VERSION 5.4 ;
NAMESCASESENSITIVE ON ;
BUSBITCHARS "[]" ;
DIVIDERCHAR "/" ;
UNITS
  DATABASE MICRONS 2000 ;
END UNITS
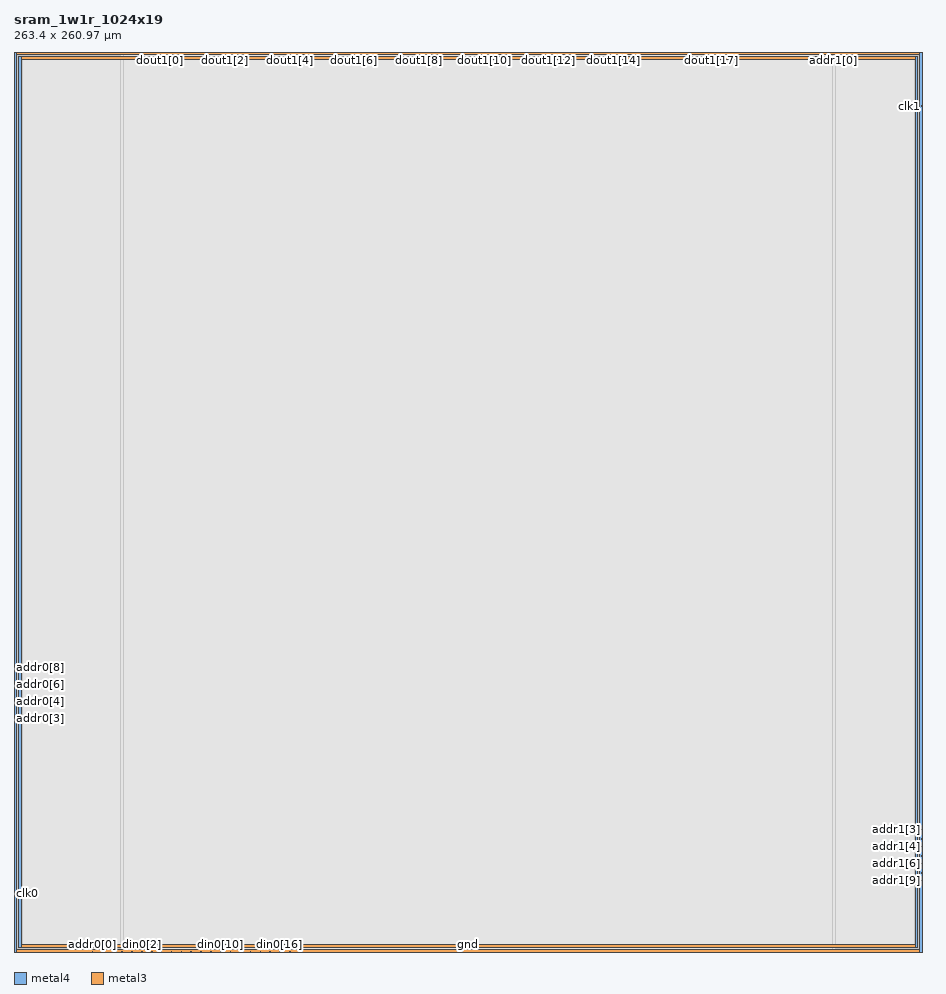
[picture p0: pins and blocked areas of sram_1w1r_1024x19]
MACRO sram_1w1r_1024x19
   CLASS BLOCK ;
   SIZE 263.4 BY 260.97 ;
   SYMMETRY X Y R90 ;
   PIN din0[0]
      DIRECTION INPUT ;
      PORT
         LAYER metal4 ;
         RECT  31.3 0.0 31.44 0.14 ;
      END
   END din0[0]
   PIN din0[1]
      DIRECTION INPUT ;
      PORT
         LAYER metal4 ;
         RECT  34.16 0.0 34.3 0.14 ;
      END
   END din0[1]
   PIN din0[2]
      DIRECTION INPUT ;
      PORT
         LAYER metal4 ;
         RECT  37.02 0.0 37.16 0.14 ;
      END
   END din0[2]
   PIN din0[3]
      DIRECTION INPUT ;
      PORT
         LAYER metal4 ;
         RECT  39.88 0.0 40.02 0.14 ;
      END
   END din0[3]
   PIN din0[4]
      DIRECTION INPUT ;
      PORT
         LAYER metal4 ;
         RECT  42.74 0.0 42.88 0.14 ;
      END
   END din0[4]
   PIN din0[5]
      DIRECTION INPUT ;
      PORT
         LAYER metal4 ;
         RECT  45.6 0.0 45.74 0.14 ;
      END
   END din0[5]
   PIN din0[6]
      DIRECTION INPUT ;
      PORT
         LAYER metal4 ;
         RECT  48.46 0.0 48.6 0.14 ;
      END
   END din0[6]
   PIN din0[7]
      DIRECTION INPUT ;
      PORT
         LAYER metal4 ;
         RECT  51.32 0.0 51.46 0.14 ;
      END
   END din0[7]
   PIN din0[8]
      DIRECTION INPUT ;
      PORT
         LAYER metal4 ;
         RECT  54.18 0.0 54.32 0.14 ;
      END
   END din0[8]
   PIN din0[9]
      DIRECTION INPUT ;
      PORT
         LAYER metal4 ;
         RECT  57.04 0.0 57.18 0.14 ;
      END
   END din0[9]
   PIN din0[10]
      DIRECTION INPUT ;
      PORT
         LAYER metal4 ;
         RECT  59.9 0.0 60.04 0.14 ;
      END
   END din0[10]
   PIN din0[11]
      DIRECTION INPUT ;
      PORT
         LAYER metal4 ;
         RECT  62.76 0.0 62.9 0.14 ;
      END
   END din0[11]
   PIN din0[12]
      DIRECTION INPUT ;
      PORT
         LAYER metal4 ;
         RECT  65.62 0.0 65.76 0.14 ;
      END
   END din0[12]
   PIN din0[13]
      DIRECTION INPUT ;
      PORT
         LAYER metal4 ;
         RECT  68.48 0.0 68.62 0.14 ;
      END
   END din0[13]
   PIN din0[14]
      DIRECTION INPUT ;
      PORT
         LAYER metal4 ;
         RECT  71.34 0.0 71.48 0.14 ;
      END
   END din0[14]
   PIN din0[15]
      DIRECTION INPUT ;
      PORT
         LAYER metal4 ;
         RECT  74.2 0.0 74.34 0.14 ;
      END
   END din0[15]
   PIN din0[16]
      DIRECTION INPUT ;
      PORT
         LAYER metal4 ;
         RECT  77.06 0.0 77.2 0.14 ;
      END
   END din0[16]
   PIN din0[17]
      DIRECTION INPUT ;
      PORT
         LAYER metal4 ;
         RECT  79.92 0.0 80.06 0.14 ;
      END
   END din0[17]
   PIN din0[18]
      DIRECTION INPUT ;
      PORT
         LAYER metal4 ;
         RECT  82.78 0.0 82.92 0.14 ;
      END
   END din0[18]
   PIN addr0[0]
      DIRECTION INPUT ;
      PORT
         LAYER metal4 ;
         RECT  22.72 0.0 22.86 0.14 ;
      END
   END addr0[0]
   PIN addr0[1]
      DIRECTION INPUT ;
      PORT
         LAYER metal4 ;
         RECT  25.58 0.0 25.72 0.14 ;
      END
   END addr0[1]
   PIN addr0[2]
      DIRECTION INPUT ;
      PORT
         LAYER metal4 ;
         RECT  28.44 0.0 28.58 0.14 ;
      END
   END addr0[2]
   PIN addr0[3]
      DIRECTION INPUT ;
      PORT
         LAYER metal3 ;
         RECT  0.0 67.6 0.14 67.74 ;
      END
   END addr0[3]
   PIN addr0[4]
      DIRECTION INPUT ;
      PORT
         LAYER metal3 ;
         RECT  0.0 70.33 0.14 70.47 ;
      END
   END addr0[4]
   PIN addr0[5]
      DIRECTION INPUT ;
      PORT
         LAYER metal3 ;
         RECT  0.0 72.54 0.14 72.68 ;
      END
   END addr0[5]
   PIN addr0[6]
      DIRECTION INPUT ;
      PORT
         LAYER metal3 ;
         RECT  0.0 75.27 0.14 75.41 ;
      END
   END addr0[6]
   PIN addr0[7]
      DIRECTION INPUT ;
      PORT
         LAYER metal3 ;
         RECT  0.0 77.48 0.14 77.62 ;
      END
   END addr0[7]
   PIN addr0[8]
      DIRECTION INPUT ;
      PORT
         LAYER metal3 ;
         RECT  0.0 80.21 0.14 80.35 ;
      END
   END addr0[8]
   PIN addr0[9]
      DIRECTION INPUT ;
      PORT
         LAYER metal3 ;
         RECT  0.0 82.42 0.14 82.56 ;
      END
   END addr0[9]
   PIN addr1[0]
      DIRECTION INPUT ;
      PORT
         LAYER metal4 ;
         RECT  237.68 260.83 237.82 260.97 ;
      END
   END addr1[0]
   PIN addr1[1]
      DIRECTION INPUT ;
      PORT
         LAYER metal4 ;
         RECT  234.82 260.83 234.96 260.97 ;
      END
   END addr1[1]
   PIN addr1[2]
      DIRECTION INPUT ;
      PORT
         LAYER metal4 ;
         RECT  231.96 260.83 232.1 260.97 ;
      END
   END addr1[2]
   PIN addr1[3]
      DIRECTION INPUT ;
      PORT
         LAYER metal3 ;
         RECT  263.26 35.49 263.4 35.63 ;
      END
   END addr1[3]
   PIN addr1[4]
      DIRECTION INPUT ;
      PORT
         LAYER metal3 ;
         RECT  263.26 32.76 263.4 32.9 ;
      END
   END addr1[4]
   PIN addr1[5]
      DIRECTION INPUT ;
      PORT
         LAYER metal3 ;
         RECT  263.26 30.55 263.4 30.69 ;
      END
   END addr1[5]
   PIN addr1[6]
      DIRECTION INPUT ;
      PORT
         LAYER metal3 ;
         RECT  263.26 27.82 263.4 27.96 ;
      END
   END addr1[6]
   PIN addr1[7]
      DIRECTION INPUT ;
      PORT
         LAYER metal3 ;
         RECT  263.26 25.61 263.4 25.75 ;
      END
   END addr1[7]
   PIN addr1[8]
      DIRECTION INPUT ;
      PORT
         LAYER metal3 ;
         RECT  263.26 22.88 263.4 23.02 ;
      END
   END addr1[8]
   PIN addr1[9]
      DIRECTION INPUT ;
      PORT
         LAYER metal3 ;
         RECT  263.26 20.67 263.4 20.81 ;
      END
   END addr1[9]
   PIN csb0
      DIRECTION INPUT ;
      PORT
         LAYER metal3 ;
         RECT  0.0 16.72 0.14 16.86 ;
      END
   END csb0
   PIN csb1
      DIRECTION INPUT ;
      PORT
         LAYER metal3 ;
         RECT  263.26 245.36 263.4 245.5 ;
      END
   END csb1
   PIN clk0
      DIRECTION INPUT ;
      PORT
         LAYER metal3 ;
         RECT  0.0 16.955 0.14 17.095 ;
      END
   END clk0
   PIN clk1
      DIRECTION INPUT ;
      PORT
         LAYER metal3 ;
         RECT  263.26 245.125 263.4 245.265 ;
      END
   END clk1
   PIN dout1[0]
      DIRECTION OUTPUT ;
      PORT
         LAYER metal4 ;
         RECT  42.26 260.83 42.4 260.97 ;
      END
   END dout1[0]
   PIN dout1[1]
      DIRECTION OUTPUT ;
      PORT
         LAYER metal4 ;
         RECT  51.66 260.83 51.8 260.97 ;
      END
   END dout1[1]
   PIN dout1[2]
      DIRECTION OUTPUT ;
      PORT
         LAYER metal4 ;
         RECT  61.06 260.83 61.2 260.97 ;
      END
   END dout1[2]
   PIN dout1[3]
      DIRECTION OUTPUT ;
      PORT
         LAYER metal4 ;
         RECT  70.46 260.83 70.6 260.97 ;
      END
   END dout1[3]
   PIN dout1[4]
      DIRECTION OUTPUT ;
      PORT
         LAYER metal4 ;
         RECT  79.86 260.83 80.0 260.97 ;
      END
   END dout1[4]
   PIN dout1[5]
      DIRECTION OUTPUT ;
      PORT
         LAYER metal4 ;
         RECT  89.26 260.83 89.4 260.97 ;
      END
   END dout1[5]
   PIN dout1[6]
      DIRECTION OUTPUT ;
      PORT
         LAYER metal4 ;
         RECT  98.66 260.83 98.8 260.97 ;
      END
   END dout1[6]
   PIN dout1[7]
      DIRECTION OUTPUT ;
      PORT
         LAYER metal4 ;
         RECT  108.06 260.83 108.2 260.97 ;
      END
   END dout1[7]
   PIN dout1[8]
      DIRECTION OUTPUT ;
      PORT
         LAYER metal4 ;
         RECT  117.46 260.83 117.6 260.97 ;
      END
   END dout1[8]
   PIN dout1[9]
      DIRECTION OUTPUT ;
      PORT
         LAYER metal4 ;
         RECT  126.86 260.83 127.0 260.97 ;
      END
   END dout1[9]
   PIN dout1[10]
      DIRECTION OUTPUT ;
      PORT
         LAYER metal4 ;
         RECT  136.26 260.83 136.4 260.97 ;
      END
   END dout1[10]
   PIN dout1[11]
      DIRECTION OUTPUT ;
      PORT
         LAYER metal4 ;
         RECT  145.66 260.83 145.8 260.97 ;
      END
   END dout1[11]
   PIN dout1[12]
      DIRECTION OUTPUT ;
      PORT
         LAYER metal4 ;
         RECT  155.06 260.83 155.2 260.97 ;
      END
   END dout1[12]
   PIN dout1[13]
      DIRECTION OUTPUT ;
      PORT
         LAYER metal4 ;
         RECT  164.46 260.83 164.6 260.97 ;
      END
   END dout1[13]
   PIN dout1[14]
      DIRECTION OUTPUT ;
      PORT
         LAYER metal4 ;
         RECT  173.86 260.83 174.0 260.97 ;
      END
   END dout1[14]
   PIN dout1[15]
      DIRECTION OUTPUT ;
      PORT
         LAYER metal4 ;
         RECT  183.26 260.83 183.4 260.97 ;
      END
   END dout1[15]
   PIN dout1[16]
      DIRECTION OUTPUT ;
      PORT
         LAYER metal4 ;
         RECT  192.66 260.83 192.8 260.97 ;
      END
   END dout1[16]
   PIN dout1[17]
      DIRECTION OUTPUT ;
      PORT
         LAYER metal4 ;
         RECT  202.06 260.83 202.2 260.97 ;
      END
   END dout1[17]
   PIN dout1[18]
      DIRECTION OUTPUT ;
      PORT
         LAYER metal4 ;
         RECT  211.46 260.83 211.6 260.97 ;
      END
   END dout1[18]
   PIN vdd
      DIRECTION INOUT ;
      USE POWER ; 
      SHAPE ABUTMENT ; 
      PORT
         LAYER metal3 ;
         RECT  0.0 260.27 263.4 260.97 ;
         LAYER metal3 ;
         RECT  0.0 0.0 263.4 0.7 ;
         LAYER metal4 ;
         RECT  0.0 0.0 0.7 260.97 ;
         LAYER metal4 ;
         RECT  262.7 0.0 263.4 260.97 ;
      END
   END vdd
   PIN gnd
      DIRECTION INOUT ;
      USE GROUND ; 
      SHAPE ABUTMENT ; 
      PORT
         LAYER metal3 ;
         RECT  1.4 258.87 262.0 259.57 ;
         LAYER metal3 ;
         RECT  1.4 1.4 262.0 2.1 ;
         LAYER metal4 ;
         RECT  261.3 1.4 262.0 259.57 ;
         LAYER metal4 ;
         RECT  1.4 1.4 2.1 259.57 ;
      END
   END gnd
   OBS
   LAYER  metal1 ;
      RECT  0.14 0.14 263.26 260.83 ;
   LAYER  metal2 ;
      RECT  0.14 0.14 263.26 260.83 ;
   LAYER  metal3 ;
      RECT  0.28 67.46 263.26 67.88 ;
      RECT  0.14 67.88 0.28 70.19 ;
      RECT  0.14 70.61 0.28 72.4 ;
      RECT  0.14 72.82 0.28 75.13 ;
      RECT  0.14 75.55 0.28 77.34 ;
      RECT  0.14 77.76 0.28 80.07 ;
      RECT  0.14 80.49 0.28 82.28 ;
      RECT  0.28 35.35 263.12 35.77 ;
      RECT  0.28 35.77 263.12 67.46 ;
      RECT  263.12 35.77 263.26 67.46 ;
      RECT  263.12 33.04 263.26 35.35 ;
      RECT  263.12 30.83 263.26 32.62 ;
      RECT  263.12 28.1 263.26 30.41 ;
      RECT  263.12 25.89 263.26 27.68 ;
      RECT  263.12 23.16 263.26 25.47 ;
      RECT  263.12 20.95 263.26 22.74 ;
      RECT  0.28 67.88 263.12 245.22 ;
      RECT  0.28 245.22 263.12 245.64 ;
      RECT  0.14 17.235 0.28 67.46 ;
      RECT  263.12 67.88 263.26 244.985 ;
      RECT  0.14 82.7 0.28 260.13 ;
      RECT  263.12 245.64 263.26 260.13 ;
      RECT  263.12 0.84 263.26 20.53 ;
      RECT  0.14 0.84 0.28 16.58 ;
      RECT  0.28 245.64 1.26 258.73 ;
      RECT  0.28 258.73 1.26 259.71 ;
      RECT  0.28 259.71 1.26 260.13 ;
      RECT  1.26 245.64 262.14 258.73 ;
      RECT  1.26 259.71 262.14 260.13 ;
      RECT  262.14 245.64 263.12 258.73 ;
      RECT  262.14 258.73 263.12 259.71 ;
      RECT  262.14 259.71 263.12 260.13 ;
      RECT  0.28 0.84 1.26 1.26 ;
      RECT  0.28 1.26 1.26 2.24 ;
      RECT  0.28 2.24 1.26 35.35 ;
      RECT  1.26 0.84 262.14 1.26 ;
      RECT  1.26 2.24 262.14 35.35 ;
      RECT  262.14 0.84 263.12 1.26 ;
      RECT  262.14 1.26 263.12 2.24 ;
      RECT  262.14 2.24 263.12 35.35 ;
   LAYER  metal4 ;
      RECT  31.02 0.42 31.72 260.83 ;
      RECT  31.72 0.14 33.88 0.42 ;
      RECT  34.58 0.14 36.74 0.42 ;
      RECT  37.44 0.14 39.6 0.42 ;
      RECT  40.3 0.14 42.46 0.42 ;
      RECT  43.16 0.14 45.32 0.42 ;
      RECT  46.02 0.14 48.18 0.42 ;
      RECT  48.88 0.14 51.04 0.42 ;
      RECT  51.74 0.14 53.9 0.42 ;
      RECT  54.6 0.14 56.76 0.42 ;
      RECT  57.46 0.14 59.62 0.42 ;
      RECT  60.32 0.14 62.48 0.42 ;
      RECT  63.18 0.14 65.34 0.42 ;
      RECT  66.04 0.14 68.2 0.42 ;
      RECT  68.9 0.14 71.06 0.42 ;
      RECT  71.76 0.14 73.92 0.42 ;
      RECT  74.62 0.14 76.78 0.42 ;
      RECT  77.48 0.14 79.64 0.42 ;
      RECT  80.34 0.14 82.5 0.42 ;
      RECT  23.14 0.14 25.3 0.42 ;
      RECT  26.0 0.14 28.16 0.42 ;
      RECT  28.86 0.14 31.02 0.42 ;
      RECT  31.72 0.42 237.4 260.55 ;
      RECT  237.4 0.42 238.1 260.55 ;
      RECT  235.24 260.55 237.4 260.83 ;
      RECT  232.38 260.55 234.54 260.83 ;
      RECT  31.72 260.55 41.98 260.83 ;
      RECT  42.68 260.55 51.38 260.83 ;
      RECT  52.08 260.55 60.78 260.83 ;
      RECT  61.48 260.55 70.18 260.83 ;
      RECT  70.88 260.55 79.58 260.83 ;
      RECT  80.28 260.55 88.98 260.83 ;
      RECT  89.68 260.55 98.38 260.83 ;
      RECT  99.08 260.55 107.78 260.83 ;
      RECT  108.48 260.55 117.18 260.83 ;
      RECT  117.88 260.55 126.58 260.83 ;
      RECT  127.28 260.55 135.98 260.83 ;
      RECT  136.68 260.55 145.38 260.83 ;
      RECT  146.08 260.55 154.78 260.83 ;
      RECT  155.48 260.55 164.18 260.83 ;
      RECT  164.88 260.55 173.58 260.83 ;
      RECT  174.28 260.55 182.98 260.83 ;
      RECT  183.68 260.55 192.38 260.83 ;
      RECT  193.08 260.55 201.78 260.83 ;
      RECT  202.48 260.55 211.18 260.83 ;
      RECT  211.88 260.55 231.68 260.83 ;
      RECT  0.98 0.14 22.44 0.42 ;
      RECT  83.2 0.14 262.42 0.42 ;
      RECT  238.1 260.55 262.42 260.83 ;
      RECT  238.1 0.42 261.02 1.12 ;
      RECT  238.1 1.12 261.02 259.85 ;
      RECT  238.1 259.85 261.02 260.55 ;
      RECT  261.02 0.42 262.28 1.12 ;
      RECT  261.02 259.85 262.28 260.55 ;
      RECT  262.28 0.42 262.42 1.12 ;
      RECT  262.28 1.12 262.42 259.85 ;
      RECT  262.28 259.85 262.42 260.55 ;
      RECT  0.98 0.42 1.12 1.12 ;
      RECT  0.98 1.12 1.12 259.85 ;
      RECT  0.98 259.85 1.12 260.83 ;
      RECT  1.12 0.42 2.38 1.12 ;
      RECT  1.12 259.85 2.38 260.83 ;
      RECT  2.38 0.42 31.02 1.12 ;
      RECT  2.38 1.12 31.02 259.85 ;
      RECT  2.38 259.85 31.02 260.83 ;
   END
END    sram_1w1r_1024x19
END    LIBRARY
